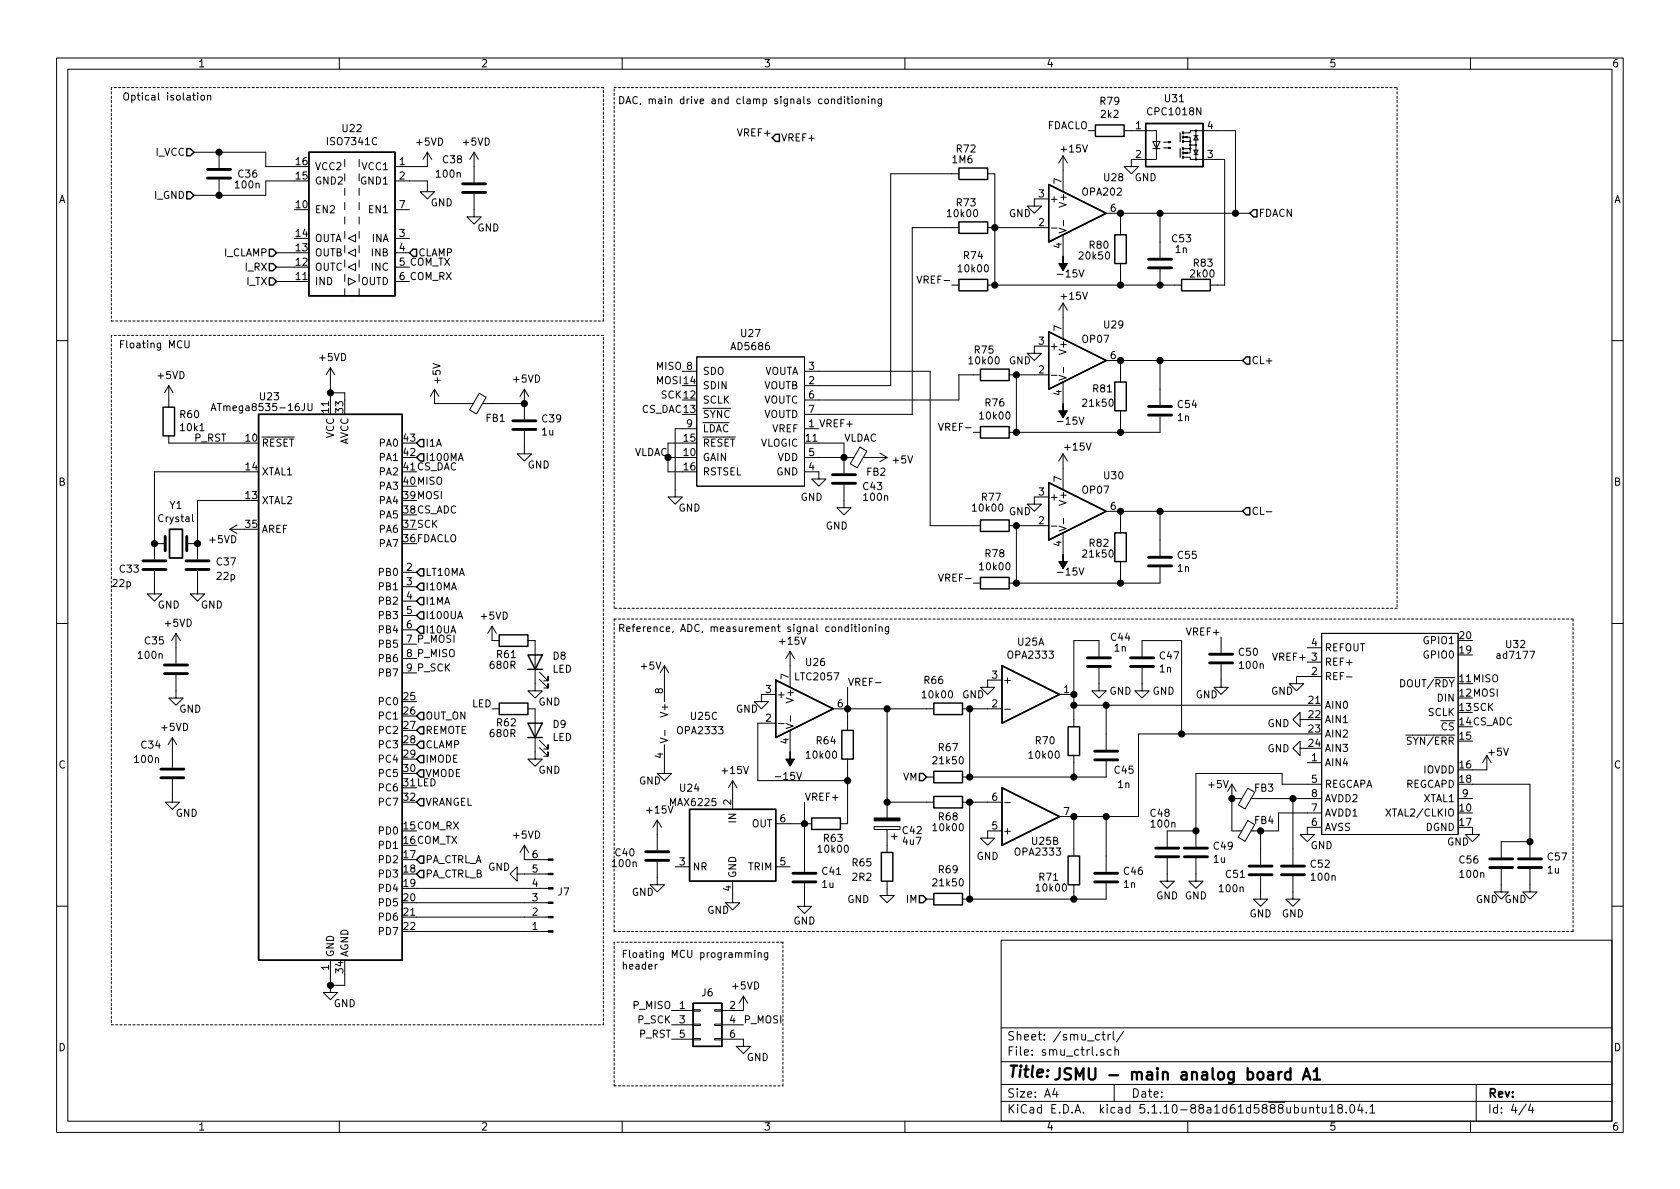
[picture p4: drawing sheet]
<svg xmlns="http://www.w3.org/2000/svg" width="297mm" height="210mm" viewBox="0 0 297 210" stroke-linecap="round" stroke-linejoin="round" font-family="sans-serif">
<defs><g id="words">
<text font-size="2.8" x="178" y="190.5">Title: JSMU - main analog board A1</text>
<g font-size="2.1">
<text x="178" y="184">Sheet: /smu_ctrl/</text>
<text x="178" y="186.7">File: smu_ctrl.sch</text>
<text x="178" y="196.9">KiCad E.D.A. kicad 5.1.10-88a1d61d5888ubuntu18.04.1</text>
<text x="178" y="194.1">Size: A4</text>
<text x="200" y="194.1">Date:</text>
<text x="263" y="194.1">Rev:</text>
<text x="263" y="196.9">Id: 4/4</text>
</g>
<g font-size="1.8">
<text x="35" y="11.9">1</text>
<text x="85" y="11.9">2</text>
<text x="135" y="11.9">3</text>
<text x="185" y="11.9">4</text>
<text x="235" y="11.9">5</text>
<text x="285" y="11.9">6</text>
<text x="21.6" y="17.8">Optical isolation</text>
<text x="60.6" y="23.4">U22</text>
<text x="109.2" y="18.4">DAC, main drive and clamp signals conditioning</text>
<text x="185" y="22.9">FDACLO</text>
<text x="194.6" y="18.5">R79</text>
<text x="194.7" y="20.8">2k2</text>
<text x="200.8" y="22.9">1</text>
<text x="203.2" y="20.4">CPC1018N</text>
<text x="206" y="18.1">U31</text>
<text x="213.5" y="22.9">4</text>
<text x="27.6" y="27.6">I_VCC</text>
<text x="52.4" y="29.2">16</text>
<text x="58.1" y="25.7">ISO7341C</text>
<text x="70.6" y="29.2">1</text>
<text x="73.7" y="25.7">+5VD</text>
<text x="78.4" y="28.9">C38</text>
<text x="82" y="25.7">+5VD</text>
<text x="130.8" y="24.1">VREF+</text>
<text x="138" y="25">VREF+</text>
<text x="168.5" y="28.9">1M6</text>
<text x="169.2" y="27">R72</text>
<text x="187.8" y="27">+15V</text>
<text x="200.8" y="27.9">2</text>
<text x="213.5" y="27.9">3</text>
<text x="10.4" y="35.9">A</text>
<text x="27.4" y="35.2">I_GND</text>
<text x="41.7" y="33.3">100n</text>
<text x="42.2" y="31.4">C36</text>
<text x="52.4" y="31.7">15</text>
<text x="55.6" y="32.6">GND2</text>
<text x="55.6" y="30.1">VCC2</text>
<text x="63.9" y="32.6">GND1</text>
<text x="64.1" y="30.1">VCC1</text>
<text x="70.6" y="31.7">2</text>
<text x="77.3" y="31.4">100n</text>
<text x="183.7" y="34.9">3</text>
<text x="185.5" y="35.8">+</text>
<text x="187.7" y="32.5" transform="rotate(-90 187.7 32.5)">7</text>
<text x="191.5" y="34.6">OPA202</text>
<text x="195.3" y="32">U28</text>
<text x="200.6" y="32">GND</text>
<text x="285.4" y="35.9">A</text>
<text x="52.4" y="36.8">10</text>
<text x="52.4" y="41.9">14</text>
<text x="55.6" y="37.7">EN2</text>
<text x="65.4" y="37.7">EN1</text>
<text x="70.6" y="41.9">3</text>
<text x="70.6" y="36.8">7</text>
<text x="76.1" y="36.5">GND</text>
<text x="84.4" y="40.9">GND</text>
<text x="167.7" y="38.4">10k00</text>
<text x="169.2" y="36.5">R73</text>
<text x="178.4" y="38.4">GND</text>
<text x="183.7" y="40">2</text>
<text x="188.6" y="36.2" transform="rotate(-90 188.6 36.2)">V+</text>
<text x="196.4" y="37.5">6</text>
<text x="222.5" y="38.3">FDACN</text>
<text x="39.6" y="45.3">I_CLAMP</text>
<text x="43.4" y="47.9">I_RX</text>
<text x="52.4" y="47">12</text>
<text x="52.4" y="44.4">13</text>
<text x="55.6" y="47.9">OUTC</text>
<text x="55.6" y="45.3">OUTB</text>
<text x="55.6" y="42.8">OUTA</text>
<text x="65.8" y="42.8">INA</text>
<text x="65.8" y="45.3">INB</text>
<text x="65.8" y="47.9">INC</text>
<text x="70.6" y="44.4">4</text>
<text x="70.6" y="47">5 COM_TX</text>
<text x="73.9" y="45.3">CLAMP</text>
<text x="170.5" y="45.8">R74</text>
<text x="187.7" y="43.9" transform="rotate(-90 187.7 43.9)">4</text>
<text x="191" y="45.9">20k50</text>
<text x="192.7" y="44">R80</text>
<text x="207.3" y="42.8">C53</text>
<text x="207.9" y="44.7">1n</text>
<text x="211.1" y="47.2">R83</text>
<text x="43.6" y="50.4">I_TX</text>
<text x="52.4" y="49.5">11</text>
<text x="55.6" y="50.4">IND</text>
<text x="63.8" y="50.4">OUTD</text>
<text x="70.6" y="49.5">6 COM_RX</text>
<text x="163" y="50.2">VREF-</text>
<text x="169.6" y="48.2">10k00</text>
<text x="187.4" y="49.1">-15V</text>
<text x="187.8" y="53">+15V</text>
<text x="210.6" y="49.1">2k00</text>
<text x="131.1" y="59.6">U27</text>
<text x="187.7" y="58.5" transform="rotate(-90 187.7 58.5)">7</text>
<text x="195.3" y="58.1">U29</text>
<text x="21" y="61.6">Floating MCU</text>
<text x="56.6" y="63.8">+5VD</text>
<text x="116.1" y="65.4">MISO 8</text>
<text x="129.5" y="61.9">AD5686</text>
<text x="143" y="65.4">3</text>
<text x="171.5" y="64.4">10k00</text>
<text x="172.4" y="62.5">R75</text>
<text x="178.4" y="64.4">GND</text>
<text x="183.7" y="61">3</text>
<text x="185.5" y="61.8">+</text>
<text x="188.6" y="62.3" transform="rotate(-90 188.6 62.3)">V+</text>
<text x="191.5" y="60.6">OP07</text>
<text x="196.4" y="63.5">6</text>
<text x="221.2" y="64.4">CL+</text>
<text x="28" y="67">+5VD</text>
<text x="46" y="70.8">U23</text>
<text x="77.9" y="67.7" transform="rotate(-90 77.9 67.7)">+5V</text>
<text x="90.9" y="67.7">+5VD</text>
<text x="116.1" y="67.9">MOSI 14</text>
<text x="116.9" y="70.5">SCK 12</text>
<text x="124.2" y="71.4">SCLK</text>
<text x="124.2" y="68.8">SDIN</text>
<text x="124.2" y="66.3">SDO</text>
<text x="135" y="68.8">VOUTB</text>
<text x="135" y="66.3">VOUTA</text>
<text x="135" y="71.4">VOUTC</text>
<text x="143" y="67.9">2</text>
<text x="143" y="70.5">6</text>
<text x="174.3" y="71.9">R76</text>
<text x="183.7" y="66">2</text>
<text x="187.7" y="69.9" transform="rotate(-90 187.7 69.9)">4</text>
<text x="191.7" y="71.9">21k50</text>
<text x="193.3" y="69.4">R81</text>
<text x="31.9" y="73.9">R60</text>
<text x="32.1" y="76.2">10k1</text>
<text x="38.5" y="72.7">ATmega8535-16JU</text>
<text x="58.2" y="73" transform="rotate(-90 58.2 73)">11</text>
<text x="59.1" y="77.5" transform="rotate(-90 59.1 77.5)">VCC</text>
<text x="60.7" y="73" transform="rotate(-90 60.7 73)">33</text>
<text x="86" y="74.6">FB1</text>
<text x="95.9" y="77">1u</text>
<text x="95.9" y="74.7">C39</text>
<text x="113.4" y="73">CS_DAC 13</text>
<text x="121.4" y="75.6">9</text>
<text x="124.2" y="73.9">SYNC</text>
<text x="124.2" y="76.4">LDAC</text>
<text x="135" y="73.9">VOUTD</text>
<text x="136.5" y="76.4">VREF</text>
<text x="143" y="75.6">1 VREF+</text>
<text x="143" y="73">7</text>
<text x="166.8" y="76.2">VREF-</text>
<text x="173.4" y="74.2">10k00</text>
<text x="187.4" y="75.1">-15V</text>
<text x="208.3" y="74.5">1n</text>
<text x="208.3" y="72.2">C54</text>
<text x="34.3" y="78.1">P_RST</text>
<text x="43.5" y="78.1">10</text>
<text x="43.5" y="83.2">14</text>
<text x="46.2" y="79">RESET</text>
<text x="61.6" y="78.8" transform="rotate(-90 61.6 78.8)">AVCC</text>
<text x="67.2" y="81.5">PA1</text>
<text x="67.2" y="79">PA0</text>
<text x="71.4" y="83.2">41CS_DAC</text>
<text x="71.4" y="80.6">42</text>
<text x="71.4" y="78.1">43</text>
<text x="75.2" y="81.5">I100MA</text>
<text x="75.2" y="79">I1A</text>
<text x="93.3" y="82.8">GND</text>
<text x="112" y="80.6">VLDAC</text>
<text x="121" y="80.6">10</text>
<text x="121" y="78.1">15</text>
<text x="121" y="83.2">16</text>
<text x="124.2" y="81.5">GAIN</text>
<text x="124.2" y="79">RESET</text>
<text x="134.4" y="79">VLOGIC</text>
<text x="137.5" y="81.5">VDD</text>
<text x="142.5" y="78.1">11</text>
<text x="143" y="83.2">4</text>
<text x="143" y="80.6">5</text>
<text x="149.2" y="78.1">VLDAC</text>
<text x="158" y="82">+5V</text>
<text x="188.4" y="79.7">+15V</text>
<text x="10.4" y="85.9">B</text>
<text x="43.5" y="88.3">13</text>
<text x="46.2" y="89.1">XTAL2</text>
<text x="46.2" y="84.1">XTAL1</text>
<text x="67.2" y="89.1">PA4</text>
<text x="67.2" y="86.6">PA3</text>
<text x="67.2" y="84.1">PA2</text>
<text x="71.4" y="88.3">39MOSI</text>
<text x="71.4" y="85.7">40MISO</text>
<text x="124.2" y="84.1">RSTSEL</text>
<text x="137.3" y="84.1">GND</text>
<text x="141.6" y="88.6">GND</text>
<text x="152.7" y="86.7">C43</text>
<text x="152.9" y="88.6">100n</text>
<text x="153.3" y="84.1">FB2</text>
<text x="173.6" y="88.6">R77</text>
<text x="183.7" y="87.6">3</text>
<text x="185.5" y="88.5">+</text>
<text x="187.7" y="85.2" transform="rotate(-90 187.7 85.2)">7</text>
<text x="188.6" y="88.9" transform="rotate(-90 188.6 88.9)">V+</text>
<text x="191.5" y="87.3">OP07</text>
<text x="195.3" y="84.8">U30</text>
<text x="285.4" y="85.9">B</text>
<text x="28.1" y="92.3">Crystal</text>
<text x="30" y="90">Y1</text>
<text x="43.5" y="93.3">35</text>
<text x="46.2" y="94.2">AREF</text>
<text x="67.2" y="94.2">PA6</text>
<text x="67.2" y="91.7">PA5</text>
<text x="71.4" y="95.9">36FDACLO</text>
<text x="71.4" y="93.3">37SCK</text>
<text x="71.4" y="90.8">38CS_ADC</text>
<text x="120" y="90.5">GND</text>
<text x="146" y="93.6">GND</text>
<text x="172.2" y="90.5">10k00</text>
<text x="178.4" y="91.1">GND</text>
<text x="183.7" y="92.7">2</text>
<text x="196.4" y="90.2">6</text>
<text x="221.2" y="91.1">CL-</text>
<text x="21.2" y="101.3">C33</text>
<text x="37.1" y="96.1">+5VD</text>
<text x="38.4" y="100">C37</text>
<text x="67.2" y="101.8">PB0</text>
<text x="67.2" y="96.8">PA7</text>
<text x="71.9" y="101">2</text>
<text x="75.2" y="101.8">LT10MA</text>
<text x="173.4" y="100.9">10k00</text>
<text x="174.3" y="98.5">R78</text>
<text x="187.4" y="101.8">-15V</text>
<text x="187.7" y="96.6" transform="rotate(-90 187.7 96.6)">4</text>
<text x="191.7" y="98.6">21k50</text>
<text x="192.7" y="96.7">R82</text>
<text x="208.3" y="101.1">1n</text>
<text x="208.3" y="98.8">C55</text>
<text x="20" y="103.8">22p</text>
<text x="27.9" y="107.6">GND</text>
<text x="35.5" y="107.6">GND</text>
<text x="38.4" y="102.5">22p</text>
<text x="67.2" y="104.4">PB1</text>
<text x="67.2" y="106.9">PB2</text>
<text x="71.9" y="103.5">3</text>
<text x="71.9" y="106">4</text>
<text x="75.2" y="104.4">I10MA</text>
<text x="75.2" y="106.9">I1MA</text>
<text x="166.8" y="102.9">VREF-</text>
<text x="25.7" y="114">C35</text>
<text x="29.3" y="110.8">+5VD</text>
<text x="67.2" y="109.5">PB3</text>
<text x="67.2" y="112">PB4</text>
<text x="71.9" y="108.6">5</text>
<text x="71.9" y="111.1">6</text>
<text x="71.9" y="113.7">7 P_MOSI</text>
<text x="75.2" y="109.5">I100UA</text>
<text x="75.2" y="112">I10UA</text>
<text x="85.1" y="109.6">+5VD</text>
<text x="109.2" y="111.8">Reference, ADC, measurement signal conditioning</text>
<text x="196.5" y="113.3">C44</text>
<text x="210.2" y="112.4">VREF+</text>
<text x="251.9" y="113.9">GPIO1</text>
<text x="258.1" y="113">20</text>
<text x="24.6" y="116.5">100n</text>
<text x="67.2" y="114.5">PB5</text>
<text x="67.2" y="117.1">PB6</text>
<text x="67.2" y="119.6">PB7</text>
<text x="71.9" y="116.2">8 P_MISO</text>
<text x="71.9" y="118.7">9 P_SCK</text>
<text x="86.8" y="118.3">680R</text>
<text x="87.9" y="116.4">R61</text>
<text x="97.7" y="119">LED</text>
<text x="97.8" y="116.7">D8</text>
<text x="113.4" y="118.4">+5V</text>
<text x="138" y="114">+15V</text>
<text x="142.6" y="117.8">U26</text>
<text x="178.4" y="116.5">OPA2333</text>
<text x="180" y="114.2">U25A</text>
<text x="197.1" y="115.2">1n</text>
<text x="205.1" y="118.9">1n</text>
<text x="205.1" y="116.6">C47</text>
<text x="219.1" y="116">C50</text>
<text x="219.3" y="118.3">100n</text>
<text x="225.4" y="116.8">VREF+ 3</text>
<text x="231.9" y="119.4">2</text>
<text x="231.9" y="114.3">4</text>
<text x="234.2" y="117.7">REF+</text>
<text x="234.2" y="115.2">REFOUT</text>
<text x="251.9" y="116.5">GPIO0</text>
<text x="258.1" y="115.6">19</text>
<text x="265" y="116.5">ad7177</text>
<text x="266.3" y="114.6">U32</text>
<text x="67.2" y="124.7">PC0</text>
<text x="71.4" y="123.8">25</text>
<text x="83.5" y="125.1">LED</text>
<text x="95.2" y="124.8">GND</text>
<text x="117.2" y="122.7" transform="rotate(-90 117.2 122.7)">8</text>
<text x="135.4" y="122.5">3</text>
<text x="137.3" y="123.4">+</text>
<text x="139.4" y="120.1" transform="rotate(-90 139.4 120.1)">7</text>
<text x="140.3" y="123.9" transform="rotate(-90 140.3 123.9)">V+</text>
<text x="140.8" y="120.3">LTC2057</text>
<text x="148.1" y="125.1">6</text>
<text x="149.9" y="121.3">VREF-</text>
<text x="163.3" y="123.5">10k00</text>
<text x="163.5" y="120.9">R66</text>
<text x="170.1" y="123.5">GND</text>
<text x="175.4" y="125.1">2</text>
<text x="175.4" y="120">3</text>
<text x="177.3" y="120.9">+</text>
<text x="188.1" y="122.5">1</text>
<text x="196.2" y="122.9">GND</text>
<text x="203.8" y="122.9">GND</text>
<text x="211.4" y="123.5">GND</text>
<text x="224.7" y="122.9">GND</text>
<text x="231.4" y="124.5">21</text>
<text x="234.2" y="120.3">REF-</text>
<text x="234.2" y="125.3">AIN0</text>
<text x="248.1" y="121.5">DOUT/RDY</text>
<text x="254.3" y="124.1">DIN</text>
<text x="258.1" y="120.6">11MISO</text>
<text x="258.1" y="123.2">12MOSI</text>
<text x="258.1" y="125.7">13SCK</text>
<text x="28.6" y="129.3">+5VD</text>
<text x="31.7" y="126">GND</text>
<text x="67.2" y="127.2">PC1</text>
<text x="67.2" y="129.8">PC2</text>
<text x="71.4" y="126.4">26</text>
<text x="71.4" y="128.9">27</text>
<text x="71.4" y="131.4">28</text>
<text x="75.2" y="127.2">OUT_ON</text>
<text x="75.2" y="129.8">REMOTE</text>
<text x="86.8" y="130.3">680R</text>
<text x="87.9" y="128.4">R62</text>
<text x="97.7" y="131">LED</text>
<text x="97.8" y="128.7">D9</text>
<text x="118.1" y="126.4" transform="rotate(-90 118.1 126.4)">V+</text>
<text x="119.9" y="129.8">OPA2333</text>
<text x="122.2" y="127.3">U25C</text>
<text x="130.1" y="126">GND</text>
<text x="135.4" y="127.6">2</text>
<text x="139.4" y="131.5" transform="rotate(-90 139.4 131.5)">4</text>
<text x="144.4" y="131.6">R64</text>
<text x="183.2" y="131.6">R70</text>
<text x="224.1" y="128.6">GND</text>
<text x="231.4" y="127">22</text>
<text x="231.4" y="129.5">23</text>
<text x="234.2" y="127.9">AIN1</text>
<text x="234.2" y="130.4">AIN2</text>
<text x="249.4" y="131.7">SYN/ERR</text>
<text x="252.5" y="126.6">SCLK</text>
<text x="254.8" y="129.2">CS</text>
<text x="258.1" y="128.3">14CS_ADC</text>
<text x="258.1" y="130.8">15</text>
<text x="10.4" y="135.9">C</text>
<text x="24" y="134.9">100n</text>
<text x="25" y="132.4">C34</text>
<text x="67.2" y="132.3">PC3</text>
<text x="67.2" y="134.9">PC4</text>
<text x="67.2" y="137.4">PC5</text>
<text x="71.4" y="134">29</text>
<text x="71.4" y="136.5">30</text>
<text x="75.2" y="134.9">IMODE</text>
<text x="75.2" y="137.4">VMODE</text>
<text x="75.2" y="132.3">CLAMP</text>
<text x="95.2" y="136.8">GND</text>
<text x="117.2" y="134.1" transform="rotate(-90 117.2 134.1)">4</text>
<text x="127.8" y="136.9">+15V</text>
<text x="137.5" y="137.9">-15V</text>
<text x="142.8" y="134.2">10k00</text>
<text x="165.2" y="135.1">21k50</text>
<text x="166" y="132.8">R67</text>
<text x="182.1" y="134.2">10k00</text>
<text x="197.1" y="136.8">C45</text>
<text x="224.1" y="133">GND</text>
<text x="231.4" y="132.1">24</text>
<text x="231.9" y="134.6">1</text>
<text x="234.2" y="135.5">AIN4</text>
<text x="234.2" y="133">AIN3</text>
<text x="251.7" y="136.8">IOVDD</text>
<text x="258.1" y="135.9">16</text>
<text x="263.3" y="133.6">+5V</text>
<text x="285.4" y="135.9">C</text>
<text x="67.2" y="139.9">PC6</text>
<text x="67.2" y="142.5">PC7</text>
<text x="71.4" y="139.1">31LED</text>
<text x="71.4" y="141.6">32</text>
<text x="75.2" y="142.5">VRANGEL</text>
<text x="113" y="138.7">GND</text>
<text x="114.5" y="143.9">+15V</text>
<text x="118.6" y="142.5">MAX6225</text>
<text x="120.3" y="140">U24</text>
<text x="129.3" y="142.3" transform="rotate(-90 129.3 142.3)">2</text>
<text x="142.2" y="141.6">VREF+</text>
<text x="159.7" y="138">VM</text>
<text x="175.4" y="141.6">6</text>
<text x="197.7" y="139.4">1n</text>
<text x="213.8" y="139.4">+5V</text>
<text x="221.8" y="140">FB3</text>
<text x="231.9" y="138.4">5</text>
<text x="231.9" y="143.5">7</text>
<text x="231.9" y="141">8</text>
<text x="234.2" y="139.3">REGCAPA</text>
<text x="234.2" y="141.9">AVDD2</text>
<text x="248.5" y="139.3">REGCAPD</text>
<text x="251.7" y="141.9">XTAL1</text>
<text x="258.1" y="143.5">10</text>
<text x="258.1" y="138.4">18</text>
<text x="258.6" y="141">9</text>
<text x="31.1" y="144.4">GND</text>
<text x="67.2" y="147.6">PD0</text>
<text x="71.4" y="146.7">15COM_RX</text>
<text x="71.4" y="149.2">16COM_TX</text>
<text x="90.9" y="148.3">+5VD</text>
<text x="130.2" y="145.4" transform="rotate(-90 130.2 145.4)">IN</text>
<text x="132.9" y="146.3">OUT</text>
<text x="137.9" y="145.4">6</text>
<text x="145.7" y="148.9">R63</text>
<text x="159.7" y="147.5">C42</text>
<text x="159.7" y="149.4">4u7</text>
<text x="165.2" y="147">10k00</text>
<text x="166" y="145.1">R68</text>
<text x="175.4" y="146.7">5</text>
<text x="177.3" y="147.6">+</text>
<text x="182.5" y="149.4">U25B</text>
<text x="188.1" y="144.1">7</text>
<text x="203.5" y="144.4">C48</text>
<text x="203.7" y="146.3">100n</text>
<text x="221.8" y="145.7">FB4</text>
<text x="231.9" y="146">6</text>
<text x="234.2" y="146.9">AVSS</text>
<text x="234.2" y="144.4">AVDD1</text>
<text x="245.7" y="144.4">XTAL2/CLKIO</text>
<text x="252.1" y="146.9">DGND</text>
<text x="255.9" y="149.5">GND</text>
<text x="258.1" y="146">17</text>
<text x="67.2" y="150.1">PD1</text>
<text x="67.2" y="152.6">PD2</text>
<text x="67.2" y="155.2">PD3</text>
<text x="71.4" y="151.8">17</text>
<text x="71.4" y="154.3">18</text>
<text x="75.2" y="152.6">PA_CTRL_A</text>
<text x="75.2" y="155.2">PA_CTRL_B</text>
<text x="86.3" y="154">GND</text>
<text x="94.1" y="154.3">5</text>
<text x="94.1" y="151.8">6</text>
<text x="108.4" y="153.3">100n</text>
<text x="108.9" y="151.4">C40</text>
<text x="120.2" y="153">3</text>
<text x="122.4" y="153.9">NR</text>
<text x="130.2" y="155.3" transform="rotate(-90 130.2 155.3)">GND</text>
<text x="132.3" y="153.9">TRIM</text>
<text x="137.9" y="153">5</text>
<text x="144.9" y="150.8">10k00</text>
<text x="145.4" y="154.7">C41</text>
<text x="150.8" y="153.2">R65</text>
<text x="150.8" y="155.7">2R2</text>
<text x="166" y="154.4">R69</text>
<text x="172.7" y="152.1">GND</text>
<text x="179.6" y="151.3">OPA2333</text>
<text x="183.8" y="155.7">R71</text>
<text x="198.8" y="154.7">C46</text>
<text x="214.6" y="152.6">1u</text>
<text x="214.7" y="150.3">C49</text>
<text x="216.8" y="155.2">C51</text>
<text x="231.7" y="150.2">GND</text>
<text x="231.8" y="153.4">C52</text>
<text x="232" y="155.7">100n</text>
<text x="258.1" y="152.7">C56</text>
<text x="258.3" y="155.2">100n</text>
<text x="273.7" y="154.5">1u</text>
<text x="273.7" y="152.2">C57</text>
<text x="67.2" y="157.7">PD4</text>
<text x="67.2" y="160.3">PD5</text>
<text x="71.4" y="156.8">19</text>
<text x="71.4" y="159.4">20</text>
<text x="71.4" y="161.9">21</text>
<text x="94.1" y="161.9">2</text>
<text x="94.1" y="159.4">3</text>
<text x="94.1" y="156.8">4</text>
<text x="98.7" y="158.4">J7</text>
<text x="111.7" y="158.4">GND</text>
<text x="125" y="161.6">GND</text>
<text x="129.3" y="157.6" transform="rotate(-90 129.3 157.6)">4</text>
<text x="145.4" y="157">1u</text>
<text x="149.8" y="159.7">GND</text>
<text x="160.4" y="159.6">IM</text>
<text x="165.2" y="156.7">21k50</text>
<text x="183.4" y="157.7">10k00</text>
<text x="198.7" y="157">1n</text>
<text x="204.4" y="159">GND GND</text>
<text x="215.7" y="157.8">100n</text>
<text x="260.9" y="159.7">GND GND</text>
<text x="67.2" y="162.8">PD6</text>
<text x="67.2" y="165.3">PD7</text>
<text x="71.4" y="164.5">22</text>
<text x="94.1" y="164.5">1</text>
<text x="140.3" y="163.5">GND</text>
<text x="220.9" y="162.2">GND</text>
<text x="226.6" y="162.2">GND</text>
<text x="58.2" y="171.5" transform="rotate(-90 58.2 171.5)">1</text>
<text x="59.1" y="169.3" transform="rotate(-90 59.1 169.3)">GND</text>
<text x="60.7" y="172" transform="rotate(-90 60.7 172)">34</text>
<text x="61.6" y="169.3" transform="rotate(-90 61.6 169.3)">AGND</text>
<text x="109.9" y="169.4">Floating MCU programming</text>
<text x="109.9" y="171.4">header</text>
<text x="59" y="178.1">GND</text>
<text x="112.1" y="178.4">P_MISO</text>
<text x="120.2" y="178.4">1</text>
<text x="124.1" y="176.2">J6</text>
<text x="129.1" y="178.4">2</text>
<text x="129.6" y="175">+5VD</text>
<text x="10.4" y="185.9">D</text>
<text x="112.9" y="181">P_SCK</text>
<text x="113.1" y="183.5">P_RST</text>
<text x="120.2" y="181">3</text>
<text x="120.2" y="183.5">5</text>
<text x="129.1" y="181">4</text>
<text x="129.1" y="183.5">6</text>
<text x="131.4" y="181">P_MOSI</text>
<text x="285.4" y="185.9">D</text>
<text x="132" y="187.6">GND</text>
<text x="35" y="199.9">1</text>
<text x="85" y="199.9">2</text>
<text x="135" y="199.9">3</text>
<text x="185" y="199.9">4</text>
<text x="235" y="199.9">5</text>
<text x="285" y="199.9">6</text>
</g>
</g></defs>
<g fill="none" stroke="#000" stroke-width=".18">
<path d="M10 10.3h277v189.9h-277zM12 12.2h273v186.1h-273zM35 16.4v.2M35 16.9v.8M35.6 17l.1-.1 .4 .1 .1 .5-.2 .1-.3 .1-.1-.1zM36.7 17l.2-.1h.3l.1 .8M36.7 16.9v.8M60 10.3v1.9M110 10.3v1.9M147 17.6l.2-.1h.3l.1 .8M148.7 17.5h-.3l-.3 .2 .1 .6h.5M148.7 17.1v1.2"/>
<path d="M149.3 17.1v.1M149.3 17.5v.8M149.7 17.5h.5M149.9 17.1v1.1l.3 .1M150.6 17.1v.1M150.6 17.5v.8M151.3 17.5h.3l.3 .2-.2 .6h-.3l-.2-.2zM152.4 17.6l.2-.1h.3l.1 .8M152.4 17.5v.8M153.5 17.1v.1M153.5 17.5v.8M154.2 17.6l.1-.1h.3l.1 .8"/>
<path d="M154.2 17.5v.8M155.9 17.5v1l-.3 .3-.3-.1M155.9 17.5h-.4l-.3 .2 .2 .6h.5M160 10.3v1.9M210 10.3v1.9M260 10.3v1.9M34.3 26.9h12.7v2.6h5.1M38.7 26.9v2.8M38.7 31.7v2.8M52.1 32h-5.1v2.5h-12.7M61 28.2v1.3M61 33.3v1.2"/>
<path d="M61 35.8v1.3M61 38.3v1.3M63.5 28.2v1.3M63.5 33.3v1.2M63.5 35.8v1.3M63.5 38.3v1.3M69.8 32h5.8v1.9h1.2l-1.2 1.3-1.3-1.3h1.3M69.8 37.1h2.6M75.6 26.9l-.8 1.3M75.6 26.9v2.6h-5.8M75.6 26.9l.7 1.3M83.8 34.3v4h1.3l-1.3 1.3-1.3-1.3h1.3"/>
<path d="M83.8 26.9l-.7 1.3M83.8 26.9v5.4M83.8 26.9l.8 1.3M169.5 30.7h-12v37.5h-15.3M174.6 30.7h1.3v19.7M185.4 35.2h-2.5v1.2h1.2l-1.2 1.3-1.3-1.3h1.3M188 27.6v6.3M188 27.6l-.8 1.2M188 27.6l.7 1.2M188 39v.9M192.4 23.1h1.3M195.6 37.7h25.4"/>
<path d="M198.1 37.7v3.8M198.8 23.1h5.7v5.1h-4.5v1.3h1.3l-1.3 1.2-1.2-1.2h1.2M203.8 25h1.3l-.6 1.3zM203.8 26.3h1.3M205.1 37.7v7.9M205.7 26.2h1.3l-.4 .1v-.3l.4 .2M205.7 25.1h1.3l-.4 .2v-.3l.4 .1M209.3 24.3h1.1v.7M209.3 27.8h1.1v.4h6.1v22.2h-2.5M209.3 25h1.1v1.3h-1.1M209.3 23.5h1.1v-.4h8v14.6M209.4 27l.5-.1v.3z"/>
<path d="M209.4 24.3l.5-.2v.3zM210.4 26.3v.7h-1.1M210.4 25.6h1.1M211.1 26.5h.7l-.3 .8zM211.1 27.3h.7M211.1 24h.7M211.5 24l.3 .8h-.7zM211.5 23.1v5.1M48.9 44.7h3.2M48.9 47.2h3.2M48.9 49.8h3.2M61 48.5v1.3"/>
<path d="M61 51v1.3M61.6 49.1l1.3 .7-1.3 .6zM61.6 47.2l1.3-.6v1.3zM61.6 44.7l1.3-.6v1.2zM61.6 42.2l1.3-.7v1.3zM63.5 40.9v1.3M63.5 43.4v1.3M63.5 46v1.2M63.5 51v1.3M69.8 42.2h2.6M69.8 44.7h2.6M69.8 47.2h2.6"/>
<path d="M69.8 49.8h2.6M162.1 48.8l.5 1.3 .4-1.3M168.3 50.4h1.2M169.5 40.3h-8.2v33h-19.1M174.6 50.4h34.3M174.6 40.3h10.8M185.9 40.3h1M187.2 40.3l1.3 .5-1.3 .4M188 41.5v3.8M188 53.6v6.3M188 53.6l-.8 1.3M188 53.6l.7 1.3"/>
<path d="M198.1 46.6v3.8M205.1 47.6v2.8M10 60.2h2M29.8 68.2l-.7 1.3M29.8 68.2v3.8M29.8 77.1v1.3h13.4M29.8 68.2l.8 1.3M32.7 60.2v1.1l.2 .2h.4l.1-.2v-1.1M37.3 72.6l.4-1.3 .5 1.3M37.5 72.3h.5M54.5 71.3v1.1l.2 .2h.2l.3-.2v-1.1M58.4 65v5.7"/>
<path d="M58.4 65l-.7 1.3M58.4 65l.8 1.3M58.4 69.5h2.6v1.2M76.8 68.8l-.7 1.3M76.8 68.8v2.6h6.9M76.8 68.8l.8 1.3M84.7 69.5l1.3 .8-1.7 2.9-1.3-.7zM85.3 71.4h7.4M92.7 76.2v4.1h1.3l-1.3 1.2-1.3-1.2h1.3M92.7 68.8l-.8 1.3M92.7 68.8v5.4M92.7 68.8l.8 1.3"/>
<path d="M120.6 65.7h2.6M120.6 78.4h-2.5v5h2.5M123.2 63.1h19v22.9h-19zM123.2 75.8h-3.8v12.1h1.2l-1.2 1.2-1.3-1.2h1.3M142.2 75.8h2.6M142.2 65.7h22.3v27.3h8.9M144.8 78.4h4.4v5.3M152 79.1l1.3 .7-1.7 2.9-1.3-.7zM165.9 74.8l.5 1.3 .4-1.3M172.1 76.4h1.3M173.4 66.3h-3.9v4.4h-27.3M178.4 66.3h7"/>
<path d="M179.7 66.3v10.1M185.4 61.2h-2.5v1.3h1.2l-1.2 1.2-1.3-1.2h1.3M185.9 66.4h1M187.2 66.4l1.3 .4-1.3 .4M188 67.6v3.8M188 65v1M195.6 63.7h24.1M198.1 63.7v3.9M198.1 72.6v3.8M205.1 73.7v2.7h-26.7M205.1 63.7v7.9M285 60.2h2"/>
<path d="M27.3 96.1h1.9M33 96.1h1.9M34 91v1.1l.2 .1M40.6 93.6l1.3 .8M40.6 93.6h2.6M41.9 92.8l-1.3 .8M43.2 83.4h-15.9v15.5M43.2 88.5h-8.3v10.4M81.1 81.5l.4-1.3 .4 1.3M118.1 80.9h2.5M142.2 83.4h2.6v1.3h1.2l-1.2 1.3-1.3-1.3h1.3M142.2 80.9h8.8"/>
<path d="M149.2 85.7v4.1h1.3l-1.3 1.3-1.2-1.3h1.2M152.7 80.9h4.1M155.6 80.1l1.2 .8M156.8 80.9l-1.2 .8M178.4 93h7M179.7 93v10.1M185.4 87.9h-2.5v1.2h1.2l-1.2 1.3-1.3-1.3h1.3M185.9 93h1M187.2 93l1.3 .5-1.3 .4M188 80.3v6.3M188 94.2v3.8M188 80.3l-.8 1.2"/>
<path d="M188 80.3l.7 1.2M188 91.7v.9M195.6 90.4h24.1M198.1 90.4v3.8M198.1 99.3v3.8M205.1 90.4v7.9M223.9 90.5h1M10 110.3h2M27.3 101v4h1.3l-1.3 1.3-1.3-1.3h1.3M31.1 119.4v4h1.3l-1.3 1.3-1.3-1.3h1.3M31.1 112v5.3M31.1 112l-.7 1.3"/>
<path d="M31.1 112l.8 1.3M34.9 101v4h1.3l-1.3 1.3-1.2-1.3h1.2M71.1 101.2h2.6M71.1 103.8h2.6M71.1 106.3h2.6M71.1 108.8h2.6M71.1 111.4h2.6M71.1 113.9h2.6M71.1 116.5h2.6M71.1 119h2.6M80.9 109.4l.5-1.3 .4 1.3M87 110.7v2.6h1.3"/>
<path d="M87 110.7l-.8 1.3M87 110.7l.8 1.3M93.3 113.3h1.3v8.9h1.3l-1.3 1.2-1.3-1.2h1.3M95.4 118.9l1.5 1.5v-.8v.8h-.8M117.5 117.7l-.8 1.3M117.5 117.7v6.4M117.5 117.7l.7 1.3M139.7 115.2l-.8 1.3M139.7 115.2v6.3M139.7 115.2l.8 1.3M150 110.9l-.4-.1-.2 .3 .1 .5h.5M150 110.4v1.3"/>
<path d="M150.6 110.4v.1M150.6 110.8v.9M151 110.8h.5M151.2 110.4v1.1l.3 .2M151.9 110.4v.1M151.9 110.8v.9M152.6 110.9l.3-.1 .2 .3-.1 .5-.3 .1-.2-.1zM153.7 111l.1-.2 .4 .1v.8M153.7 110.8v.9M154.8 110.4v.1M154.8 110.8v.9M155.4 111l.2-.2 .3 .1 .1 .8"/>
<path d="M155.4 110.8v.9M157.1 110.8v1.1l-.2 .2-.3-.1M157.1 110.9l-.3-.1-.3 .3 .1 .5h.5M165.9 101.5l.5 1.3 .4-1.3M172.1 103.1h1.3M194.3 118.1v4.1h1.3l-1.3 1.2-1.3-1.2h1.3M194.3 116.1v-2.8h-4.4v15.2M201.9 118.1v4.1h1.3l-1.3 1.2-1.2-1.2h1.2M201.9 116.1v-2.8h7v16.5M205.1 100.3v2.8h-26.7M215.9 117.5v4h1.3l-1.3 1.3-1.3-1.3h1.3M215.9 112.6v2.8"/>
<path d="M231.1 117.1h2.6M231.1 114.5h2.6M233.7 112h24.1v35.6h-24.1zM233.7 119.6h-4.5v1.3h1.3l-1.3 1.3-1.2-1.3h1.2M238.1 119.7h.9M285 110.3h2M30.5 137.8v4.1h1.2l-1.2 1.2-1.3-1.2h1.3M30.5 130.4v5.4M30.5 130.4l-.8 1.3M30.5 130.4l.7 1.3M87 125.3h1.3M93.3 125.3h1.3v8.9h1.3l-1.3 1.3-1.3-1.3h1.3"/>
<path d="M95.4 120.1l1.5 1.6v-.8v.8h-.8M95.4 132.2l1.5 1.5v-.7v.7h-.8M95.4 130.9l1.5 1.6v-.8v.8h-.8M116.8 130.5l1.2 .4-1.2 .5M117.5 131.7v5.1h1.2l-1.2 1.2-1.3-1.2h1.3M117.6 129.1v1M129.5 138l-.7 1.3M129.5 138v5.1M129.5 138l.8 1.3M137.2 122.8h-2.6v1.3h1.3l-1.3 1.2-1.3-1.2h1.3M137.2 127.9h-3.2v10.1h15.9M137.6 128h1"/>
<path d="M139 128l1.3 .4-1.3 .4M139.7 129.2v3.8M139.8 126.6v1M147.3 125.3h17.8M149.9 134.2v11.5h-1.3M149.9 121.5v7.7M154.8 120.7h1M156.8 125.3v19.3M163.8 137.4h1.3M170.2 125.3h7M171.4 125.3v12.1M177.2 120.3h-2.6v1.2h1.3l-1.3 1.3-1.2-1.3h1.2"/>
<path d="M177.6 125.4h1M187.3 122.8h2.6M189.9 133.6v3.8M189.9 124.7h41.2M195.6 124.7v7.9M195.6 134.6v2.8h-25.4M217.8 138.7l-.8 1.2M217.8 138.7v8.2h1.8M217.8 138.7l.8 1.2M220.6 139.4l1.2 .7-1.7 2.9-1.2-.7zM229.9 127.2v-1.2l-1.3 1.2 1.3 1.3v-1.3h1.2M229.9 132.3v-1.2l-1.3 1.2 1.3 1.3v-1.3h1.2"/>
<path d="M231.1 129.8h-29.8v14.6h-14M231.1 134.9h2.6M233.7 138.7h-7v-1.9h-15.2v12.9M248.6 130h1.2M249.5 130.4l-.5-.1-.1 .2v.4l.6 .2v.3l-.2 .2h-.5M260.3 138.7h10.2v12.9M262.9 133.6l-.8 1.3M262.9 133.6v2.5h-2.6M262.9 133.6l.8 1.3M73.7 157.1h23.2M73.7 159.6h23.2M91.4 154.6v-1.3l-1.2 1.3 1.2 1.2v-1.2h5.5"/>
<path d="M92.7 149.5v2.5h4.2M92.7 149.5l-.8 1.2M92.7 149.5l.8 1.2M116.2 152.4v4.1h1.3l-1.3 1.2-1.3-1.2h1.3M116.2 145v5.4M116.2 145l-.8 1.3M116.2 145l.8 1.3M119.4 153.3h2.5M129.5 155.8v3.8h1.3l-1.3 1.3-1.2-1.3h1.2M137.2 145.7h6.3M137.2 153.3h2.5M142.2 156.2v4.1h1.3l-1.3 1.2-1.2-1.2h1.2"/>
<path d="M142.2 141.9v12.3M154.6 146.2h4.5v.5h-4.5zM156.8 155.8v2.6h1.3l-1.3 1.2-1.2-1.2h1.2M156.8 146.7v4M156.8 141.9h8.3M157.6 147.9h1M158.1 147.4v1.1M163.8 159h1.3M170.2 141.9h7M171.4 141.9v17.1M177.2 146.9h-2.6v1.3h1.3l-1.3 1.3-1.2-1.3h1.2M177.6 141.9h1"/>
<path d="M189.9 144.4v7M189.9 156.5v2.5M195.6 156.2v2.8h-25.4M195.6 144.4v9.8M206.4 151.8v4h1.2l-1.2 1.3-1.3-1.3h1.3M211.5 151.8v4h1.2l-1.2 1.3-1.3-1.3h1.3M211.5 146.9h-5.1v2.8M217.8 141.2h1.8M220.6 145.1l1.2 .7-1.7 3-1.2-.7zM221.2 141.2h12.5M222.9 154.9v4.1h1.3l-1.3 1.3-1.3-1.3h1.3M222.9 146.9v6"/>
<path d="M228.6 154.9v4.1h1.3l-1.3 1.3-1.3-1.3h1.3M228.6 141.2v11.7M233.7 146.3h-2.6v1.3h1.3l-1.3 1.2-1.2-1.2h1.2M233.7 143.8h-7.6v3.1h-4.9M245.1 143l.8 1.3M245.9 143l-.8 1.3M257.8 141.2h2.5M260.3 146.3v1.3h1.3l-1.3 1.2-1.2-1.2h1.2M265.4 153.7v4h1.3l-1.3 1.3-1.2-1.3h1.2M270.5 153.7v4h1.3l-1.3 1.3-1.3-1.3h1.3M270.5 148.8h-5.1v2.8M10 160.2h2"/>
<path d="M58.4 174.2v1.3h1.3l-1.3 1.3-1.3-1.3h1.3M58.4 169.8v4.4M61 172.3v1.9h-2.6M73.7 162.2h23.2M73.7 164.7h23.2M116.2 170.5l-.4 .3M118.7 178.7h3.9M122.6 178.6h1.2v.2h-1.2zM126.4 178.6h1.2v.2h-1.2zM131.4 176.1v2.6h-3.8M131.4 176.1l-.7 1.3M131.4 176.1l.8 1.3"/>
<path d="M131.7 168.6l.2-.1h.3l.1 .8M132.3 168.7l.2-.2h.3v.8M133.5 168v.2M133.5 168.5v.8M134.1 168.6l.1-.1h.3l.1 .8M134.1 168.5v.8M135.7 168.5v1.1l-.2 .1h-.3M135.7 168.5h-.3l-.3 .2 .2 .6h.4M177 166.3h108v32h-108zM285 160.2h2M60 198.3v1.9M110 198.3v1.9"/>
<path d="M118.7 181.2h3.9M118.7 183.8h3.9M122.6 183.6h1.2v.3h-1.2zM122.6 181.1h1.2v.3h-1.2zM126.4 183.6h1.2v.3h-1.2zM126.4 181.1h1.2v.3h-1.2zM127.6 183.8h3.8v1.2h1.3l-1.3 1.3-1.2-1.3h1.2M127.6 181.2h3.8M160 198.3v1.9M177 194.8h108M177 191.8h108M177 187.8h108"/>
<path d="M177 181.8h108M186.5 192.5l-.4 1h1M186.8 193v1M194.8 182.9h.6M195 182.4v1.3l.4 .2M195.1 185.7l-.3-.1-.2 .2v.2l.5 .2v.3h-.5M195.9 182.9v1M196.3 182.9l-.4 .3M196.5 185.7l-.4-.1-.3 .3v.6l.3 .1 .4-.1M196.8 182.4v1.3l.3 .2M197 191.8v3M197.1 185.7l.2-.1 .4 .1 .1 .9"/>
<path d="M197.1 185.1v1.5M198.7 182.3l-1.3 2M210 198.3v1.9M231.6 196l.2-.2 .4 .1v.9M231.6 195.8v1M232.7 195.8h.6M232.9 195.3v1.3l.4 .2M233.8 195.8l.1 .9 .3 .1 .2-.1M234.4 195.8v1M235.1 195.8l.4-.5v1.5M235.1 196.8h.8M236.8 196l-.2-.2v-.3a.48 .48 0 0 1 .6-.1l.2 .2-.2 .3-.5 .1-.2 .3 .1 .4 .2 .1h.3l.3-.3v-.2l-.3-.3"/>
<path d="M238 196.7v.1M238.8 195.5l.3-.2a.94 .94 0 0 1 0 1.5 .82 .82 0 0 1-.3-1.3zM240.4 195.2l-.3 1.1h.9M240.8 195.8v1M241.6 196.7v.1M242.2 195.8l.4-.5v1.5M242.2 196.8h.9M260 198.3v1.9M261 191.8v6.5M269.8 195.2l-1.2 2M270.6 195.2l-.3 1.1h.9M271 195.8v1"/>
<circle cx="210.4" cy="26.3" r=".13"/>
<circle cx="210.4" cy="25.6" r=".13"/>
<circle cx="210.4" cy="25" r=".13"/>
<circle cx="211.5" cy="25.6" r=".13"/>
<circle cx="211.5" cy="28.2" r=".13"/>
<circle cx="211.5" cy="23.1" r=".13"/>
</g>
<g fill="none" stroke="#000" stroke-width=".25">
<path d="M33 26.3h.7l.6 .6-.6 .7h-.7zM33 33.9h.7l.6 .6-.6 .7h-.7zM54.6 26.9h15.2v25.4h-15.2zM137.2 23.7h.6v1.3h-.6l-.7-.6zM169.5 39.2h5.1v2.1h-5.1zM169.5 29.7h5.1v2h-5.1zM185.4 32.6l10.2 5.1-10.2 5.1zM193.7 22.1h5.1v2h-5.1zM202.6 21.8h10.1v7.7h-10.1zM221.6 37.1h.6v1.2h-.6l-.6-.6zM47.6 49.1h.7l.6 .7-.6 .6h-.7zM47.6 46.6h.7l.6 .6-.6 .7h-.7z"/>
<path d="M47.6 44.1h.7l.6 .6-.6 .6h-.7zM73 44.1h.7v1.2h-.7l-.6-.6zM169.5 49.4h5.1v2h-5.1zM185.4 58.7l10.2 5-10.2 5.1zM197.1 41.5h2v5.1h-2zM208.9 49.4h5.1v2h-5.1zM28.8 72h2.1v5.1h-2.1zM45.7 73.3h25.4v96.5h-25.4zM74.3 77.7h.6v1.3h-.6l-.6-.6zM173.4 65.3h5v2h-5zM173.4 75.4h5v2.1h-5zM197.1 67.6h2v5h-2z"/>
<path d="M220.3 63.1h.7v1.3h-.7l-.6-.7zM74.3 80.3h.6v1.2h-.6l-.6-.6zM173.4 91.9h5v2.1h-5zM185.4 85.3l10.2 5.1-10.2 5.1zM197.1 94.2h2v5.1h-2zM220.3 89.8h.7v1.3h-.7l-.6-.7zM74.3 103.1h.6v1.3h-.6l-.6-.6zM74.3 105.7h.6v1.2h-.6l-.6-.6zM74.3 108.2h.6v1.3h-.6l-.6-.7zM74.3 110.7h.6v1.3h-.6l-.6-.6zM74.3 100.6h.6v1.2h-.6l-.6-.6zM88.3 112.3h5v2h-5z"/>
<path d="M93.3 115.8h2.6l-1.3 2.6zM93.3 118.4h2.6M173.4 102.1h5v2h-5zM177.2 117.7l10.1 5.1-10.1 5.1zM74.3 126h.6v1.2h-.6l-.6-.6zM74.3 133.6h.6v1.3h-.6l-.6-.7zM74.3 128.5h.6v1.3h-.6l-.6-.6zM74.3 136.1h.6v1.3h-.6l-.6-.6zM74.3 131.1h.6v1.2h-.6l-.6-.6zM88.3 124.3h5v2.1h-5zM93.3 127.9h2.6l-1.3 2.5zM93.3 130.4h2.6"/>
<path d="M137.2 120.3l10.1 5-10.1 5.1zM148.8 129.2h2.1v5h-2.1zM162.6 136.8h.6l.6 .6-.6 .6h-.6zM165.1 124.3h5.1v2.1h-5.1zM165.1 136.4h5.1v2h-5.1zM177.2 139.3l10.1 5.1-10.1 5.1zM188.8 128.5h2.1v5.1h-2.1zM74.3 151.4h.6v1.2h-.6l-.6-.6zM74.3 153.9h.6v1.3h-.6l-.6-.6zM74.3 141.2h.6v1.3h-.6l-.6-.6zM121.9 143.1h15.3v12.7h-15.3zM143.5 144.6h5.1v2.1h-5.1z"/>
<path d="M155.8 150.7h2.1v5.1h-2.1zM162.6 158.4h.6l.6 .6-.6 .6h-.6zM165.1 158h5.1v2h-5.1zM165.1 140.8h5.1v2.1h-5.1zM188.8 151.4h2.1v5.1h-2.1zM122.6 177.4h5v7.6h-5z"/>
</g>
<g fill="none" stroke="#000" stroke-width=".51">
<path d="M36.7 31.5h4.1M36.7 30h4.1M81.8 34h4.1M81.8 32.5h4.1M203.1 47.4h4M203.1 45.8h4M90.7 75.9h4M90.7 74.4h4M203.1 73.4h4M203.1 71.9h4M25.3 99.2h4M29.2 94.9v2.5"/>
<path d="M32.9 99.2h4.1M33 94.9v2.5M147.2 85.5h4.1M147.2 83.9h4.1M203.1 98.5h4M25.3 100.7h4M29.1 119.1h4M29.1 117.6h4M32.9 100.7h4.1M192.3 117.9h4M192.3 116.3h4M199.9 117.9h4.1"/>
<path d="M199.9 116.3h4.1M203.1 100.1h4M213.9 117.2h4M213.9 115.7h4M28.4 137.5h4.1M28.4 136h4.1M193.5 134.4h4.1M193.5 132.8h4.1M114.2 152.1h4M114.2 150.6h4M140.2 156h4.1M140.2 154.4h4.1"/>
<path d="M193.5 156h4.1M193.5 154.4h4.1M204.3 151.5h4.1M204.3 150h4.1M209.4 151.5h4.1M209.4 150h4.1M220.9 154.7h4M220.9 153.2h4M226.6 154.7h4M226.6 153.2h4M263.4 153.4h4.1M263.4 151.9h4.1"/>
<path d="M268.5 153.4h4M268.5 151.9h4"/>
</g>
<path d="M208.7 23.5v1.5M208.7 26.3v1.5" fill="none" stroke="#000" stroke-width=".2"/>
<path d="M209.2 27.7v.2M209.2 26.9v.3M209.2 24.9v.2M209.2 24.1v.3M209.2 23.4v.2M209.2 26.2v.2" fill="none" stroke="#000" stroke-width=".36"/>
<path d="M188 45.3v1.3h.7l-.7 1.3-.8-1.3h.8zM188 71.4v1.2h.7l-.7 1.3-.8-1.3h.8zM188 98v1.3h.7l-.7 1.3-.8-1.3h.8zM139.7 133v1.2h.8l-.8 1.3-.8-1.3h.8zM96.9 151.9h.9v.2h-.9zM96.9 154.4h.9v.3h-.9zM96.9 157h.9v.2h-.9zM96.9 159.5h.9v.3h-.9zM154.6 144.6h4.5v.6h-4.5zM96.9 162h.9v.3h-.9zM96.9 164.6h.9v.2h-.9z" fill="#000" stroke="#000" stroke-width=".18"/>
<path d="M30 93.6h2.3v5.1h-2.3z" fill="none" stroke="#000" stroke-width=".3"/>
<g fill="none" stroke="#000" stroke-width=".18" stroke-dasharray=".4 .4">
<path d="M19.7 15.5v41.3M106.7 15.5h-87M108.6 15.5h138.4M247 15.5v92.1M19.7 56.8h87M19.7 59.3v121.9M106.7 56.8v-41.3M106.7 59.3h-87M108.6 107.6v-92.1M108.6 109.5h169.5M247 107.6h-138.4M278.1 109.5v55.2"/>
<path d="M108.6 164.7h169.5M108.6 164.7v-55.2M108.6 166.6v25.4M138.4 166.6h-29.8M19.7 181.2h87M106.7 181.2v-121.9M108.6 192h29.8M138.4 192v-25.4"/>
</g>
<path d="M226.1 189.6v1.3M226.6 189.6l-.4 .1-.1 .2M228.2 189.7l-.6-.1-.4 .3v.6l.2 .3 .2 .1 .6-.1M228.2 188.9v2M230.4 190.9l.6-2 .7 2M230.6 190.3h.9M232.3 189.5l.5-.6v2M232.3 190.9h1.1" fill="none" stroke="#000" stroke-width=".41"/>
<g fill="#000" stroke="#000" stroke-width=".25">
<circle cx="38.7" cy="26.9" r=".51"/>
<circle cx="38.7" cy="34.5" r=".51"/>
<circle cx="198.1" cy="37.7" r=".51"/>
<circle cx="205.1" cy="37.7" r=".51"/>
<circle cx="218.4" cy="37.7" r=".51"/>
<circle cx="175.9" cy="50.4" r=".51"/>
<circle cx="175.9" cy="40.3" r=".51"/>
<circle cx="198.1" cy="50.4" r=".51"/>
<circle cx="205.1" cy="50.4" r=".51"/>
<circle cx="58.4" cy="69.5" r=".51"/>
<circle cx="92.7" cy="71.4" r=".51"/>
<circle cx="179.7" cy="66.3" r=".51"/>
<circle cx="179.7" cy="76.4" r=".51"/>
<circle cx="198.1" cy="76.4" r=".51"/>
<circle cx="198.1" cy="63.7" r=".51"/>
<circle cx="205.1" cy="63.7" r=".51"/>
<circle cx="27.3" cy="96.1" r=".51"/>
<circle cx="34.9" cy="96.1" r=".51"/>
<circle cx="118.1" cy="80.9" r=".51"/>
<circle cx="149.2" cy="80.9" r=".51"/>
<circle cx="179.7" cy="93" r=".51"/>
<circle cx="198.1" cy="90.4" r=".51"/>
<circle cx="205.1" cy="90.4" r=".51"/>
<circle cx="179.7" cy="103.1" r=".51"/>
<circle cx="198.1" cy="103.1" r=".51"/>
<circle cx="149.9" cy="125.3" r=".51"/>
<circle cx="149.9" cy="138" r=".51"/>
<circle cx="156.8" cy="125.3" r=".51"/>
<circle cx="171.5" cy="125.3" r=".51"/>
<circle cx="171.5" cy="137.4" r=".51"/>
<circle cx="189.9" cy="122.8" r=".51"/>
<circle cx="189.9" cy="124.7" r=".51"/>
<circle cx="189.9" cy="137.4" r=".51"/>
<circle cx="195.6" cy="124.7" r=".51"/>
<circle cx="208.9" cy="129.8" r=".51"/>
<circle cx="142.2" cy="145.7" r=".51"/>
<circle cx="156.8" cy="141.9" r=".51"/>
<circle cx="171.5" cy="159" r=".51"/>
<circle cx="171.5" cy="141.9" r=".51"/>
<circle cx="189.9" cy="159" r=".51"/>
<circle cx="189.9" cy="144.4" r=".51"/>
<circle cx="195.6" cy="144.4" r=".51"/>
<circle cx="211.5" cy="146.9" r=".51"/>
<circle cx="217.8" cy="141.2" r=".51"/>
<circle cx="222.9" cy="146.9" r=".51"/>
<circle cx="228.6" cy="141.2" r=".51"/>
<circle cx="270.5" cy="148.8" r=".51"/>
<circle cx="58.4" cy="174.2" r=".51"/>
</g>
<use href="#words"/>
</svg>
